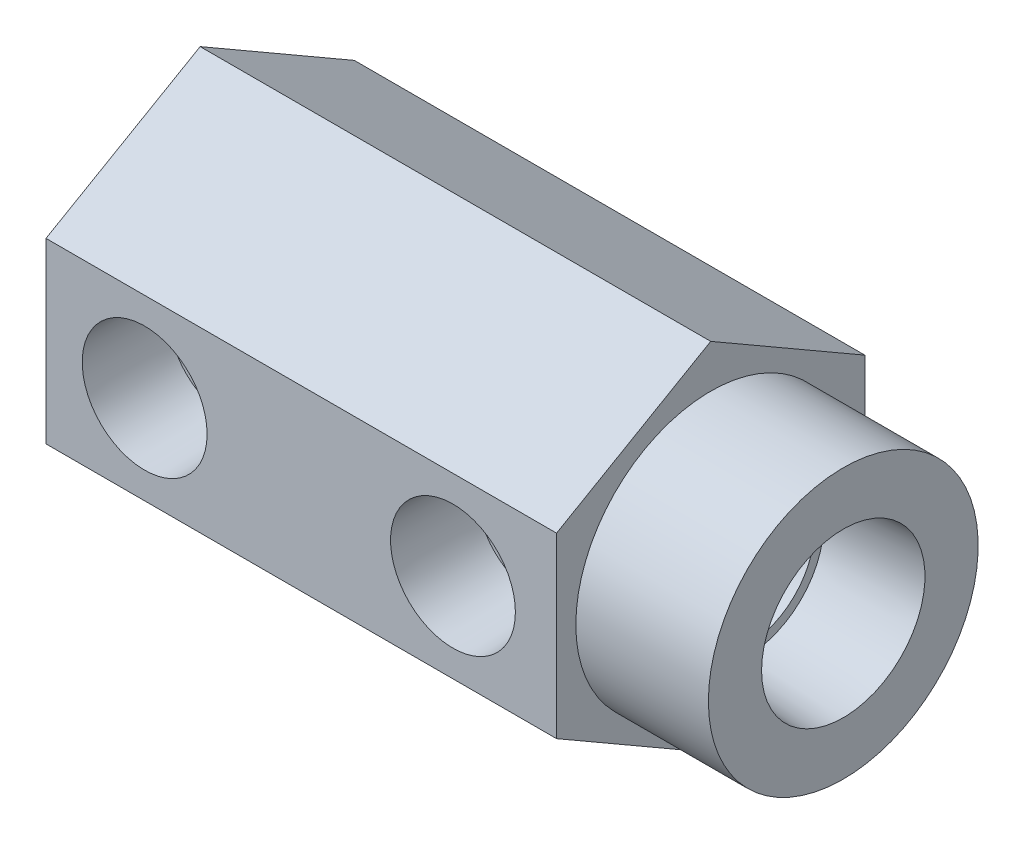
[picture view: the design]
ISO-10303-21;
HEADER;
FILE_DESCRIPTION(('STEP AP214'),'2;1');
FILE_NAME('part.step','',(''),(''),'','','');
FILE_SCHEMA(('AUTOMOTIVE_DESIGN { 1 0 10303 214 1 1 1 1 }'));
ENDSEC;
DATA;
#1=APPLICATION_CONTEXT('core data for automotive mechanical design processes');
#2=APPLICATION_PROTOCOL_DEFINITION('international standard','automotive_design',2000,#1);
#3=PRODUCT_CONTEXT('',#1,'mechanical');
#4=PRODUCT('Part','Part','',(#3));
#5=PRODUCT_RELATED_PRODUCT_CATEGORY('part','',(#4));
#6=PRODUCT_DEFINITION_FORMATION('','',#4);
#7=PRODUCT_DEFINITION_CONTEXT('part definition',#1,'design');
#8=PRODUCT_DEFINITION('design','',#6,#7);
#9=PRODUCT_DEFINITION_SHAPE('','',#8);
#10=(LENGTH_UNIT() NAMED_UNIT(*) SI_UNIT(.MILLI.,.METRE.));
#11=(NAMED_UNIT(*) PLANE_ANGLE_UNIT() SI_UNIT($,.RADIAN.));
#12=(NAMED_UNIT(*) SI_UNIT($,.STERADIAN.) SOLID_ANGLE_UNIT());
#13=UNCERTAINTY_MEASURE_WITH_UNIT(LENGTH_MEASURE(1.E-05),#10,'distance_accuracy_value','');
#14=(GEOMETRIC_REPRESENTATION_CONTEXT(3) GLOBAL_UNCERTAINTY_ASSIGNED_CONTEXT((#13)) GLOBAL_UNIT_ASSIGNED_CONTEXT((#10,
#11,#12)) REPRESENTATION_CONTEXT('',''));
#15=CARTESIAN_POINT('',(0.,0.,0.));
#16=DIRECTION('',(0.,0.,1.));
#17=DIRECTION('',(1.,0.,0.));
#18=AXIS2_PLACEMENT_3D('',#15,#16,#17);
#19=CARTESIAN_POINT('',(52.9844,0.,0.));
#20=DIRECTION('',(1.,0.,0.));
#21=DIRECTION('',(0.,0.,-1.));
#22=AXIS2_PLACEMENT_3D('',#19,#20,#21);
#23=CYLINDRICAL_SURFACE('',#22,3.17499999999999);
#24=CARTESIAN_POINT('',(16.4084,0.,0.));
#25=DIRECTION('',(1.,0.,0.));
#26=DIRECTION('',(0.,0.,-1.));
#27=AXIS2_PLACEMENT_3D('',#24,#25,#26);
#28=CIRCLE('',#27,3.17499999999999);
#29=CARTESIAN_POINT('',(16.4084,0.,-3.17499999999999));
#30=VERTEX_POINT('',#29);
#31=EDGE_CURVE('E145',#30,#30,#28,.T.);
#32=ORIENTED_EDGE('',*,*,#31,.F.);
#33=EDGE_LOOP('',(#32));
#34=FACE_BOUND('',#33,.T.);
#35=CARTESIAN_POINT('',(27.5844,0.,0.));
#36=DIRECTION('',(1.,0.,0.));
#37=DIRECTION('',(0.,0.,-1.));
#38=AXIS2_PLACEMENT_3D('',#35,#36,#37);
#39=CIRCLE('',#38,3.17499999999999);
#40=CARTESIAN_POINT('',(27.5844,0.,-3.17499999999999));
#41=VERTEX_POINT('',#40);
#42=EDGE_CURVE('E39',#41,#41,#39,.F.);
#43=ORIENTED_EDGE('',*,*,#42,.F.);
#44=EDGE_LOOP('',(#43));
#45=FACE_BOUND('',#44,.T.);
#46=ADVANCED_FACE('F35',(#34,#45),#23,.F.);
#47=CARTESIAN_POINT('',(33.528,0.,12.7));
#48=DIRECTION('',(0.,0.,1.));
#49=DIRECTION('',(1.,0.,0.));
#50=AXIS2_PLACEMENT_3D('',#47,#48,#49);
#51=CYLINDRICAL_SURFACE('',#50,4.2164);
#52=CARTESIAN_POINT('',(33.528,0.,5.77596));
#53=DIRECTION('',(0.,0.,1.));
#54=DIRECTION('',(1.,0.,0.));
#55=AXIS2_PLACEMENT_3D('',#52,#53,#54);
#56=CIRCLE('',#55,4.2164);
#57=CARTESIAN_POINT('',(37.7444,0.,5.77596));
#58=VERTEX_POINT('',#57);
#59=EDGE_CURVE('E286',#58,#58,#56,.T.);
#60=ORIENTED_EDGE('',*,*,#59,.T.);
#61=EDGE_LOOP('',(#60));
#62=FACE_BOUND('',#61,.T.);
#63=CARTESIAN_POINT('',(37.7444,0.,5.54990000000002));
#64=CARTESIAN_POINT('',(37.7443993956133,0.102666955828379,5.54989942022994));
#65=CARTESIAN_POINT('',(37.7406438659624,0.205343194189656,5.54704470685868));
#66=CARTESIAN_POINT('',(37.7256842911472,0.409877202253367,5.53569249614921));
#67=CARTESIAN_POINT('',(37.7144766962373,0.511734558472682,5.52719230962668));
#68=CARTESIAN_POINT('',(37.6847756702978,0.713930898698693,5.50472974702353));
#69=CARTESIAN_POINT('',(37.6662712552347,0.814267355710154,5.49075913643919));
#70=CARTESIAN_POINT('',(37.6222775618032,1.01254840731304,5.45767930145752));
#71=CARTESIAN_POINT('',(37.5967851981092,1.11049192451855,5.43856780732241));
#72=CARTESIAN_POINT('',(37.5107274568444,1.398497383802,5.37438339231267));
#73=CARTESIAN_POINT('',(37.440361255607,1.58418379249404,5.32229076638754));
#74=CARTESIAN_POINT('',(37.276841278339,1.93974746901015,5.2032718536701));
#75=CARTESIAN_POINT('',(37.1836912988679,2.10962736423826,5.1363480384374));
#76=CARTESIAN_POINT('',(36.9680945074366,2.44693461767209,4.98509307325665));
#77=CARTESIAN_POINT('',(36.8437265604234,2.61265837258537,4.89972096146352));
#78=CARTESIAN_POINT('',(36.5743774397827,2.92229860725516,4.72159970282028));
#79=CARTESIAN_POINT('',(36.4293655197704,3.06618188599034,4.62883964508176));
#80=CARTESIAN_POINT('',(36.1818679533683,3.27873581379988,4.47894046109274));
#81=CARTESIAN_POINT('',(36.0852396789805,3.35465016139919,4.4222195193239));
#82=CARTESIAN_POINT('',(35.8853172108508,3.49803153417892,4.30969399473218));
#83=CARTESIAN_POINT('',(35.7820209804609,3.56549595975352,4.25388969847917));
#84=CARTESIAN_POINT('',(35.5689644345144,3.69158445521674,4.14494021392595));
#85=CARTESIAN_POINT('',(35.459210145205,3.75021659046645,4.091792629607));
#86=CARTESIAN_POINT('',(35.2332788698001,3.85820397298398,3.99013143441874));
#87=CARTESIAN_POINT('',(35.1171056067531,3.90756452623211,3.94161518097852));
#88=CARTESIAN_POINT('',(34.8423535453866,4.00972513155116,3.83800214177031));
#89=CARTESIAN_POINT('',(34.6815147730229,4.05910874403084,3.78530268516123));
#90=CARTESIAN_POINT('',(34.4334747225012,4.11890503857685,3.71979682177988));
#91=CARTESIAN_POINT('',(34.3497154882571,4.13645117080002,3.70022626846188));
#92=CARTESIAN_POINT('',(34.1802742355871,4.16652842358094,3.66632583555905));
#93=CARTESIAN_POINT('',(34.0945932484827,4.17906216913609,3.65199321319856));
#94=CARTESIAN_POINT('',(33.9209530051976,4.19896788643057,3.62908998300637));
#95=CARTESIAN_POINT('',(33.8329793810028,4.2062854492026,3.62058014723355));
#96=CARTESIAN_POINT('',(33.6563570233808,4.2153732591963,3.60999553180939));
#97=CARTESIAN_POINT('',(33.5677083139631,4.21714370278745,3.60792052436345));
#98=CARTESIAN_POINT('',(33.3905433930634,4.21508975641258,3.61032018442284));
#99=CARTESIAN_POINT('',(33.3020272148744,4.21126414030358,3.61479628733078));
#100=CARTESIAN_POINT('',(33.1259748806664,4.1981195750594,3.63005192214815));
#101=CARTESIAN_POINT('',(33.038438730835,4.18880059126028,3.64083149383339));
#102=CARTESIAN_POINT('',(32.7985166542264,4.15568903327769,3.67868158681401));
#103=CARTESIAN_POINT('',(32.6478348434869,4.1262776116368,3.71190594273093));
#104=CARTESIAN_POINT('',(32.3540921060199,4.05253036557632,3.79227022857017));
#105=CARTESIAN_POINT('',(32.211039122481,4.00817932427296,3.83942434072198));
#106=CARTESIAN_POINT('',(31.9583831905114,3.91523448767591,3.93394303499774));
#107=CARTESIAN_POINT('',(31.847374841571,3.86881960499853,3.97976043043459));
#108=CARTESIAN_POINT('',(31.6311954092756,3.7675481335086,4.07576238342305));
#109=CARTESIAN_POINT('',(31.5260274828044,3.71268703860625,4.12594926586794));
#110=CARTESIAN_POINT('',(31.3214051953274,3.5948485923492,4.22901830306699));
#111=CARTESIAN_POINT('',(31.2219633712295,3.53185434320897,4.28190592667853));
#112=CARTESIAN_POINT('',(31.0290973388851,3.39812936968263,4.38878526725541));
#113=CARTESIAN_POINT('',(30.9356721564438,3.32739990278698,4.44277680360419));
#114=CARTESIAN_POINT('',(30.7523590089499,3.17621734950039,4.55214005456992));
#115=CARTESIAN_POINT('',(30.662649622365,3.09554338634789,4.60750688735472));
#116=CARTESIAN_POINT('',(30.4900225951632,2.92631985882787,4.7168012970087));
#117=CARTESIAN_POINT('',(30.4071076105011,2.83776724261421,4.77072830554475));
#118=CARTESIAN_POINT('',(30.1695373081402,2.56081846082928,4.92833957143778));
#119=CARTESIAN_POINT('',(30.0255232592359,2.36069403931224,5.02818332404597));
#120=CARTESIAN_POINT('',(29.79622654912,1.97290355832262,5.19079382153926));
#121=CARTESIAN_POINT('',(29.704976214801,1.79022627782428,5.25699864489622));
#122=CARTESIAN_POINT('',(29.5877201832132,1.50428240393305,5.34307696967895));
#123=CARTESIAN_POINT('',(29.5518975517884,1.40695118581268,5.36957042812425));
#124=CARTESIAN_POINT('',(29.487255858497,1.20882529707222,5.41761054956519));
#125=CARTESIAN_POINT('',(29.4584337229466,1.10803216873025,5.43915938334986));
#126=CARTESIAN_POINT('',(29.4080388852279,0.902877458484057,5.47696644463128));
#127=CARTESIAN_POINT('',(29.3865198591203,0.798495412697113,5.49318547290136));
#128=CARTESIAN_POINT('',(29.3513945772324,0.587711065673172,5.5197156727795));
#129=CARTESIAN_POINT('',(29.3377846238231,0.481309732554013,5.53002960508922));
#130=CARTESIAN_POINT('',(29.3187165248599,0.267379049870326,5.54449183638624));
#131=CARTESIAN_POINT('',(29.3132569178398,0.159849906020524,5.54864124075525));
#132=CARTESIAN_POINT('',(29.31059043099,-0.0553630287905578,5.55066695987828));
#133=CARTESIAN_POINT('',(29.3133828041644,-0.163046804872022,5.54854384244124));
#134=CARTESIAN_POINT('',(29.3264157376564,-0.365919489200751,5.53865106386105));
#135=CARTESIAN_POINT('',(29.3358141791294,-0.461194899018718,5.5315198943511));
#136=CARTESIAN_POINT('',(29.3609746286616,-0.65042738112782,5.51247648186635));
#137=CARTESIAN_POINT('',(29.3767386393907,-0.744384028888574,5.50056273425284));
#138=CARTESIAN_POINT('',(29.4332697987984,-1.02327908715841,5.4579792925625));
#139=CARTESIAN_POINT('',(29.4832871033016,-1.20540685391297,5.42045882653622));
#140=CARTESIAN_POINT('',(29.6070842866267,-1.56242729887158,5.32871242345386));
#141=CARTESIAN_POINT('',(29.6814572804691,-1.73700152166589,5.27407116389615));
#142=CARTESIAN_POINT('',(29.8505450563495,-2.07109183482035,5.15204916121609));
#143=CARTESIAN_POINT('',(29.9452628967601,-2.23060565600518,5.08466650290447));
#144=CARTESIAN_POINT('',(30.1694079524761,-2.55802504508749,4.92909083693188));
#145=CARTESIAN_POINT('',(30.3019810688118,-2.72300325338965,4.83929765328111));
#146=CARTESIAN_POINT('',(30.5883037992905,-3.02991540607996,4.65330404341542));
#147=CARTESIAN_POINT('',(30.7420960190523,-3.17180170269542,4.55709093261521));
#148=CARTESIAN_POINT('',(31.0034639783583,-3.3794070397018,4.40345363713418));
#149=CARTESIAN_POINT('',(31.1049126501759,-3.45288781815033,4.34591141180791));
#150=CARTESIAN_POINT('',(31.314685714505,-3.5909673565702,4.23253042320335));
#151=CARTESIAN_POINT('',(31.4230125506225,-3.65556293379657,4.17669227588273));
#152=CARTESIAN_POINT('',(31.6462598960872,-3.7753266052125,4.06875742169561));
#153=CARTESIAN_POINT('',(31.7611678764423,-3.83051186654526,4.01665400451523));
#154=CARTESIAN_POINT('',(31.9975785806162,-3.93094643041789,3.91841531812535));
#155=CARTESIAN_POINT('',(32.1190762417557,-3.97620322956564,3.87227555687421));
#156=CARTESIAN_POINT('',(32.3974988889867,-4.06520982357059,3.77896121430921));
#157=CARTESIAN_POINT('',(32.5561211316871,-4.10619306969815,3.7340128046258));
#158=CARTESIAN_POINT('',(32.7996105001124,-4.15383268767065,3.68070998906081));
#159=CARTESIAN_POINT('',(32.8816471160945,-4.16740255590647,3.66530086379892));
#160=CARTESIAN_POINT('',(33.0471718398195,-4.18972486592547,3.63976459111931));
#161=CARTESIAN_POINT('',(33.1306592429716,-4.19847958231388,3.62963494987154));
#162=CARTESIAN_POINT('',(33.2991320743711,-4.21103758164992,3.61505835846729));
#163=CARTESIAN_POINT('',(33.3841240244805,-4.21480358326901,3.6106542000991));
#164=CARTESIAN_POINT('',(33.5542775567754,-4.21717640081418,3.60788260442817));
#165=CARTESIAN_POINT('',(33.639439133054,-4.21578339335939,3.60951496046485));
#166=CARTESIAN_POINT('',(33.8092521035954,-4.20786839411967,3.61873867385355));
#167=CARTESIAN_POINT('',(33.8939031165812,-4.20134295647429,3.62633403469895));
#168=CARTESIAN_POINT('',(34.0620056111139,-4.18330254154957,3.64713005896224));
#169=CARTESIAN_POINT('',(34.1454564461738,-4.17178497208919,3.66033363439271));
#170=CARTESIAN_POINT('',(34.3240534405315,-4.1417155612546,3.69434379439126));
#171=CARTESIAN_POINT('',(34.4188890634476,-4.12232321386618,3.71603879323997));
#172=CARTESIAN_POINT('',(34.6056232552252,-4.07749843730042,3.7651699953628));
#173=CARTESIAN_POINT('',(34.697519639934,-4.05206162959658,3.79261035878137));
#174=CARTESIAN_POINT('',(34.9685718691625,-3.96719813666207,3.88193715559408));
#175=CARTESIAN_POINT('',(35.1428493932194,-3.89926066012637,3.95077814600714));
#176=CARTESIAN_POINT('',(35.426054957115,-3.76720881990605,4.07616702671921));
#177=CARTESIAN_POINT('',(35.5387046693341,-3.70824622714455,4.13006200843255));
#178=CARTESIAN_POINT('',(35.7572672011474,-3.5811127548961,4.24076863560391));
#179=CARTESIAN_POINT('',(35.8631775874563,-3.51293857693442,4.29758132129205));
#180=CARTESIAN_POINT('',(36.0681950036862,-3.36767607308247,4.41233843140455));
#181=CARTESIAN_POINT('',(36.167295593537,-3.29057948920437,4.47028386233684));
#182=CARTESIAN_POINT('',(36.3583871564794,-3.12772920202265,4.58570164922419));
#183=CARTESIAN_POINT('',(36.450379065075,-3.04197664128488,4.64317406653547));
#184=CARTESIAN_POINT('',(36.6281804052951,-2.86064113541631,4.75707411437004));
#185=CARTESIAN_POINT('',(36.7138800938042,-2.76493305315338,4.81347428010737));
#186=CARTESIAN_POINT('',(36.8770160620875,-2.56491197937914,4.9229681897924));
#187=CARTESIAN_POINT('',(36.954451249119,-2.46059785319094,4.9760614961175));
#188=CARTESIAN_POINT('',(37.100127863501,-2.24386878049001,5.07747289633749));
#189=CARTESIAN_POINT('',(37.1683863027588,-2.13146943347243,5.12579978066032));
#190=CARTESIAN_POINT('',(37.29491910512,-1.89890802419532,5.21642520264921));
#191=CARTESIAN_POINT('',(37.3531981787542,-1.77874966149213,5.25872658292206));
#192=CARTESIAN_POINT('',(37.4439058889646,-1.56622364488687,5.32513054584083));
#193=CARTESIAN_POINT('',(37.4789964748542,-1.47553606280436,5.35100662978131));
#194=CARTESIAN_POINT('',(37.5430944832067,-1.29096184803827,5.39850728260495));
#195=CARTESIAN_POINT('',(37.5721033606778,-1.19707598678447,5.420132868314));
#196=CARTESIAN_POINT('',(37.6236159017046,-1.00680382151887,5.4586756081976));
#197=CARTESIAN_POINT('',(37.6461329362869,-0.910423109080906,5.47560243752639));
#198=CARTESIAN_POINT('',(37.6844114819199,-0.715624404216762,5.50444899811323));
#199=CARTESIAN_POINT('',(37.700175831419,-0.61720728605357,5.5163708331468));
#200=CARTESIAN_POINT('',(37.7230526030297,-0.432452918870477,5.53369497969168));
#201=CARTESIAN_POINT('',(37.7310480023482,-0.34628607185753,5.53976185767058));
#202=CARTESIAN_POINT('',(37.7417225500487,-0.173415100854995,5.54786506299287));
#203=CARTESIAN_POINT('',(37.7444005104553,-0.0867108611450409,5.54990048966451));
#204=CARTESIAN_POINT('',(37.7444,0.,5.54990000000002));
#205=B_SPLINE_CURVE_WITH_KNOTS('',3,(#63,#64,#65,#66,#67,#68,#69,#70,#71,#72,#73,#74,#75,#76,
#77,#78,#79,#80,#81,#82,#83,#84,#85,#86,#87,#88,#89,#90,#91,#92,#93,#94,#95,#96,#97,#98,#99,
#100,#101,#102,#103,#104,#105,#106,#107,#108,#109,#110,#111,#112,#113,#114,#115,#116,#117,#118,
#119,#120,#121,#122,#123,#124,#125,#126,#127,#128,#129,#130,#131,#132,#133,#134,#135,#136,#137,
#138,#139,#140,#141,#142,#143,#144,#145,#146,#147,#148,#149,#150,#151,#152,#153,#154,#155,#156,
#157,#158,#159,#160,#161,#162,#163,#164,#165,#166,#167,#168,#169,#170,#171,#172,#173,#174,#175,
#176,#177,#178,#179,#180,#181,#182,#183,#184,#185,#186,#187,#188,#189,#190,#191,#192,#193,#194,
#195,#196,#197,#198,#199,#200,#201,#202,#203,#204),.UNSPECIFIED.,.T.,.F.,(4,2,2,2,2,2,2,2,2,2,2,
2,2,2,2,2,2,2,2,2,2,2,2,2,2,2,2,2,2,2,2,2,2,2,2,2,2,2,2,2,2,2,2,2,2,2,2,2,2,2,2,2,2,2,2,2,2,2,2,
2,2,2,2,2,2,2,2,2,2,2,4),(0.,0.307909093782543,0.615964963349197,0.924486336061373,
1.23314414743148,1.84608968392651,2.45893315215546,3.12888302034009,3.79984133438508,
4.20549409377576,4.61127134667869,5.01667578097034,5.42184749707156,5.94866107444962,
6.21175949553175,6.47471995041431,6.74038467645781,7.00603999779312,7.2717535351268,
7.53746874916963,8.00678580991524,8.47658235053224,8.86232249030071,9.24826914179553,
9.63503095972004,10.0217299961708,10.4195319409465,10.817488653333,11.6111347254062,
12.2523588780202,12.5731486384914,12.8937972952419,13.2167540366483,13.5395596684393,
13.8623074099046,14.1850259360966,14.4726847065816,14.7604340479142,15.3354443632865,
15.925652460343,16.5159493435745,17.2032337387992,17.891918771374,18.3050679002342,
18.7183646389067,19.1308991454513,19.543121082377,20.0506303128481,20.3040712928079,
20.5573924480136,20.8125962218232,21.0677912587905,21.323157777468,21.5786570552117,
21.8757972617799,22.1731533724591,22.7686074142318,23.1824806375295,23.5965024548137,
24.0109105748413,24.4252640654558,24.8456610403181,25.266113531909,25.6857755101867,
26.1052388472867,26.4068178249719,26.7083245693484,27.0092058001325,27.3099604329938,
27.5699574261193,27.8300124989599),.UNSPECIFIED.);
#206=CARTESIAN_POINT('',(37.7444,0.,5.54990000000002));
#207=VERTEX_POINT('',#206);
#208=EDGE_CURVE('E157',#207,#207,#205,.T.);
#209=ORIENTED_EDGE('',*,*,#208,.F.);
#210=EDGE_LOOP('',(#209));
#211=FACE_BOUND('',#210,.T.);
#212=ADVANCED_FACE('F189',(#62,#211),#51,.F.);
#213=CARTESIAN_POINT('',(52.9844,0.,0.));
#214=DIRECTION('',(1.,0.,0.));
#215=DIRECTION('',(0.,0.,-1.));
#216=AXIS2_PLACEMENT_3D('',#213,#214,#215);
#217=PLANE('',#216);
#218=CARTESIAN_POINT('',(52.9844,0.,0.));
#219=DIRECTION('',(1.,0.,0.));
#220=DIRECTION('',(0.,0.,-1.));
#221=AXIS2_PLACEMENT_3D('',#218,#219,#220);
#222=CIRCLE('',#221,11.1125);
#223=CARTESIAN_POINT('',(52.9844,0.,11.1125));
#224=VERTEX_POINT('',#223);
#225=EDGE_CURVE('E279',#224,#224,#222,.T.);
#226=ORIENTED_EDGE('',*,*,#225,.T.);
#227=EDGE_LOOP('',(#226));
#228=FACE_BOUND('',#227,.T.);
#229=CARTESIAN_POINT('',(52.9844,0.,0.));
#230=DIRECTION('',(-1.,0.,0.));
#231=DIRECTION('',(0.,0.,1.));
#232=AXIS2_PLACEMENT_3D('',#229,#230,#231);
#233=CIRCLE('',#232,6.73100000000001);
#234=CARTESIAN_POINT('',(52.9844,0.,6.73100000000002));
#235=VERTEX_POINT('',#234);
#236=EDGE_CURVE('E311',#235,#235,#233,.T.);
#237=ORIENTED_EDGE('',*,*,#236,.T.);
#238=EDGE_LOOP('',(#237));
#239=FACE_BOUND('',#238,.T.);
#240=ADVANCED_FACE('F233',(#228,#239),#217,.T.);
#241=CARTESIAN_POINT('',(16.4084,0.,0.));
#242=DIRECTION('',(1.,0.,0.));
#243=DIRECTION('',(0.,0.,-1.));
#244=AXIS2_PLACEMENT_3D('',#241,#242,#243);
#245=CONICAL_SURFACE('',#244,3.17499999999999,1.02974425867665);
#246=CARTESIAN_POINT('',(16.1699334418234,0.,0.));
#247=DIRECTION('',(1.,0.,0.));
#248=DIRECTION('',(0.,0.,-1.));
#249=AXIS2_PLACEMENT_3D('',#246,#247,#248);
#250=CIRCLE('',#249,2.77812499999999);
#251=CARTESIAN_POINT('',(16.1699334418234,0.,-2.77812499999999));
#252=VERTEX_POINT('',#251);
#253=EDGE_CURVE('E142',#252,#252,#250,.F.);
#254=ORIENTED_EDGE('',*,*,#253,.T.);
#255=EDGE_LOOP('',(#254));
#256=FACE_BOUND('',#255,.T.);
#257=ORIENTED_EDGE('',*,*,#31,.T.);
#258=EDGE_LOOP('',(#257));
#259=FACE_BOUND('',#258,.T.);
#260=ADVANCED_FACE('F238',(#256,#259),#245,.F.);
#261=CARTESIAN_POINT('',(52.9844,0.,0.));
#262=DIRECTION('',(1.,0.,0.));
#263=DIRECTION('',(0.,0.,-1.));
#264=AXIS2_PLACEMENT_3D('',#261,#262,#263);
#265=CYLINDRICAL_SURFACE('',#264,2.77812499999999);
#266=CARTESIAN_POINT('',(12.3444,0.,-2.77812499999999));
#267=CARTESIAN_POINT('',(12.3443955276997,-0.139883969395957,-2.77811997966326));
#268=CARTESIAN_POINT('',(12.3373755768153,-0.279800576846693,-2.76749868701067));
#269=CARTESIAN_POINT('',(12.3099836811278,-0.555187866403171,-2.72565235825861));
#270=CARTESIAN_POINT('',(12.2896031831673,-0.6906556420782,-2.69441412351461));
#271=CARTESIAN_POINT('',(12.2375104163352,-0.952754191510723,-2.61323304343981));
#272=CARTESIAN_POINT('',(12.2058514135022,-1.07942321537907,-2.56337806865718));
#273=CARTESIAN_POINT('',(12.1337605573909,-1.32210407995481,-2.44706908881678));
#274=CARTESIAN_POINT('',(12.0933275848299,-1.4381145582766,-2.38061296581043));
#275=CARTESIAN_POINT('',(12.0029110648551,-1.66718281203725,-2.22689910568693));
#276=CARTESIAN_POINT('',(11.9524106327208,-1.77917454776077,-2.13836318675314));
#277=CARTESIAN_POINT('',(11.8482905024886,-1.98773409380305,-1.94603559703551));
#278=CARTESIAN_POINT('',(11.7946664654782,-2.08427971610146,-1.84222238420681));
#279=CARTESIAN_POINT('',(11.680384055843,-2.27435151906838,-1.60375038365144));
#280=CARTESIAN_POINT('',(11.6199096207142,-2.36513867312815,-1.46680289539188));
#281=CARTESIAN_POINT('',(11.5081634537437,-2.52226630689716,-1.17614753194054));
#282=CARTESIAN_POINT('',(11.4568758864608,-2.58864906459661,-1.0224692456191));
#283=CARTESIAN_POINT('',(11.3845681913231,-2.6786449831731,-0.746661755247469));
#284=CARTESIAN_POINT('',(11.3590896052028,-2.70904686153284,-0.627927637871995));
#285=CARTESIAN_POINT('',(11.3208802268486,-2.75398593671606,-0.385574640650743));
#286=CARTESIAN_POINT('',(11.3081282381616,-2.76854951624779,-0.261964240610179));
#287=CARTESIAN_POINT('',(11.2973346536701,-2.78090423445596,-0.0127670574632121));
#288=CARTESIAN_POINT('',(11.299348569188,-2.77863208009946,0.112825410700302));
#289=CARTESIAN_POINT('',(11.3178791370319,-2.75733196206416,0.361533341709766));
#290=CARTESIAN_POINT('',(11.3344080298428,-2.73828985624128,0.484646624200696));
#291=CARTESIAN_POINT('',(11.3785253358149,-2.68574292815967,0.720261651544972));
#292=CARTESIAN_POINT('',(11.405649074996,-2.65284171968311,0.832990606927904));
#293=CARTESIAN_POINT('',(11.4678512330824,-2.57408907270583,1.05144792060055));
#294=CARTESIAN_POINT('',(11.5029322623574,-2.52823338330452,1.15717396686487));
#295=CARTESIAN_POINT('',(11.5855849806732,-2.41433509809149,1.38122293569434));
#296=CARTESIAN_POINT('',(11.6342504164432,-2.34368656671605,1.49781446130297));
#297=CARTESIAN_POINT('',(11.7342078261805,-2.18677186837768,1.71883915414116));
#298=CARTESIAN_POINT('',(11.7855029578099,-2.10048659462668,1.82325718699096));
#299=CARTESIAN_POINT('',(11.8972440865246,-1.89401186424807,2.0389531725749));
#300=CARTESIAN_POINT('',(11.9574048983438,-1.77049887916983,2.14723280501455));
#301=CARTESIAN_POINT('',(12.0697093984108,-1.50393214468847,2.3416440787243));
#302=CARTESIAN_POINT('',(12.1218609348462,-1.360897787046,2.42779745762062));
#303=CARTESIAN_POINT('',(12.2035712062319,-1.08804954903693,2.55975410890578));
#304=CARTESIAN_POINT('',(12.2355572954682,-0.961193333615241,2.61016446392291));
#305=CARTESIAN_POINT('',(12.2881429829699,-0.699302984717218,2.69216201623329));
#306=CARTESIAN_POINT('',(12.3087520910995,-0.564275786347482,2.72376493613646));
#307=CARTESIAN_POINT('',(12.3367594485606,-0.289077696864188,2.76656311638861));
#308=CARTESIAN_POINT('',(12.3441045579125,-0.148888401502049,2.77767629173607));
#309=CARTESIAN_POINT('',(12.3446777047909,0.131592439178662,2.77854678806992));
#310=CARTESIAN_POINT('',(12.3379061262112,0.271883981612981,2.76830468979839));
#311=CARTESIAN_POINT('',(12.3118222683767,0.53898974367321,2.72846498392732));
#312=CARTESIAN_POINT('',(12.293354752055,0.666086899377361,2.70017031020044));
#313=CARTESIAN_POINT('',(12.2462164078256,0.913332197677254,2.62686914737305));
#314=CARTESIAN_POINT('',(12.2175439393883,1.03347921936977,2.58185997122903));
#315=CARTESIAN_POINT('',(12.1499536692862,1.27211922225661,2.47345398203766));
#316=CARTESIAN_POINT('',(12.1104913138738,1.38999773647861,2.40905262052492));
#317=CARTESIAN_POINT('',(12.0252151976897,1.61372348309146,2.26530005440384));
#318=CARTESIAN_POINT('',(11.9793972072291,1.7195626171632,2.18593888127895));
#319=CARTESIAN_POINT('',(11.8769809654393,1.93374575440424,2.00042955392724));
#320=CARTESIAN_POINT('',(11.819819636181,2.03987372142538,1.89203198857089));
#321=CARTESIAN_POINT('',(11.7060872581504,2.23336504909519,1.65921349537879));
#322=CARTESIAN_POINT('',(11.6495165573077,2.32071788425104,1.53478364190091));
#323=CARTESIAN_POINT('',(11.5483307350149,2.46707513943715,1.28464793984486));
#324=CARTESIAN_POINT('',(11.5030847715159,2.52806065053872,1.16036269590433));
#325=CARTESIAN_POINT('',(11.4230252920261,2.63156603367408,0.901230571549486));
#326=CARTESIAN_POINT('',(11.3881929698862,2.67411925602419,0.766403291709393));
#327=CARTESIAN_POINT('',(11.3387874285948,2.7331509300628,0.511839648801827));
#328=CARTESIAN_POINT('',(11.321811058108,2.75278516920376,0.393313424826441));
#329=CARTESIAN_POINT('',(11.3012384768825,2.77648205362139,0.153603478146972));
#330=CARTESIAN_POINT('',(11.2976297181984,2.78055930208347,0.0324223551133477));
#331=CARTESIAN_POINT('',(11.3043444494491,2.77288356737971,-0.209018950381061));
#332=CARTESIAN_POINT('',(11.3146671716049,2.76113145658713,-0.329279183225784));
#333=CARTESIAN_POINT('',(11.347667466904,2.7225709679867,-0.565663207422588));
#334=CARTESIAN_POINT('',(11.3703613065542,2.6957427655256,-0.681781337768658));
#335=CARTESIAN_POINT('',(11.4329033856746,2.61891416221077,-0.939151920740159));
#336=CARTESIAN_POINT('',(11.4757744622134,2.564531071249,-1.07834904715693));
#337=CARTESIAN_POINT('',(11.5704785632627,2.43592687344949,-1.34390911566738));
#338=CARTESIAN_POINT('',(11.6223239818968,2.36167825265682,-1.47025391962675));
#339=CARTESIAN_POINT('',(11.7301621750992,2.19375835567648,-1.71092773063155));
#340=CARTESIAN_POINT('',(11.7862104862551,2.09977824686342,-1.82501585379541));
#341=CARTESIAN_POINT('',(11.8966286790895,1.89448963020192,-2.03733294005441));
#342=CARTESIAN_POINT('',(11.9509980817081,1.78317623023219,-2.13555740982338));
#343=CARTESIAN_POINT('',(12.0599078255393,1.52949387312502,-2.32521006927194));
#344=CARTESIAN_POINT('',(12.1136453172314,1.38498877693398,-2.41431318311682));
#345=CARTESIAN_POINT('',(12.1837916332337,1.15543155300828,-2.52789646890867));
#346=CARTESIAN_POINT('',(12.205427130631,1.07679625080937,-2.5624074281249));
#347=CARTESIAN_POINT('',(12.2445786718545,0.915786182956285,-2.62426099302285));
#348=CARTESIAN_POINT('',(12.2620964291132,0.833412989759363,-2.6516065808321));
#349=CARTESIAN_POINT('',(12.2990312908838,0.628891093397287,-2.70889840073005));
#350=CARTESIAN_POINT('',(12.3159311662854,0.505095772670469,-2.73475594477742));
#351=CARTESIAN_POINT('',(12.3386147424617,0.254208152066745,-2.76936720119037));
#352=CARTESIAN_POINT('',(12.3444040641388,0.127117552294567,-2.77812956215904));
#353=CARTESIAN_POINT('',(12.3444,0.,-2.77812499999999));
#354=B_SPLINE_CURVE_WITH_KNOTS('',3,(#266,#267,#268,#269,#270,#271,#272,#273,#274,#275,#276,
#277,#278,#279,#280,#281,#282,#283,#284,#285,#286,#287,#288,#289,#290,#291,#292,#293,#294,#295,
#296,#297,#298,#299,#300,#301,#302,#303,#304,#305,#306,#307,#308,#309,#310,#311,#312,#313,#314,
#315,#316,#317,#318,#319,#320,#321,#322,#323,#324,#325,#326,#327,#328,#329,#330,#331,#332,#333,
#334,#335,#336,#337,#338,#339,#340,#341,#342,#343,#344,#345,#346,#347,#348,#349,#350,#351,#352,
#353),.UNSPECIFIED.,.T.,.F.,(4,2,2,2,2,2,2,2,2,2,2,2,2,2,2,2,2,2,2,2,2,2,2,2,2,2,2,2,2,2,2,2,2,
2,2,2,2,2,2,2,2,2,2,4),(0.,0.419152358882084,0.838573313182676,1.25603913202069,
1.67355823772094,2.12613857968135,2.57936331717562,3.10216790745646,3.62406247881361,
3.99811472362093,4.37154293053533,4.74637573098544,5.12152493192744,5.48179405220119,
5.84218152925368,6.27490955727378,6.70816995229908,7.23044654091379,7.75220804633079,
8.17104864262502,8.58953860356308,9.0097014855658,9.4298529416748,9.82266301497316,
10.2155362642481,10.6339311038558,11.0526057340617,11.5370187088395,12.0217025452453,
12.4570234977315,12.8915534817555,13.253952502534,13.6160112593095,13.9780500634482,
14.3405660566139,14.8044889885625,15.2690578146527,15.7415272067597,16.2141301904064,
16.744910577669,17.0101944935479,17.2753678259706,17.656459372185,18.0373580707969),.UNSPECIFIED.);
#355=CARTESIAN_POINT('',(12.3444,0.,-2.77812499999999));
#356=VERTEX_POINT('',#355);
#357=EDGE_CURVE('E147',#356,#356,#354,.T.);
#358=ORIENTED_EDGE('',*,*,#357,.T.);
#359=EDGE_LOOP('',(#358));
#360=FACE_BOUND('',#359,.T.);
#361=ORIENTED_EDGE('',*,*,#253,.F.);
#362=EDGE_LOOP('',(#361));
#363=FACE_BOUND('',#362,.T.);
#364=ADVANCED_FACE('F163',(#360,#363),#265,.F.);
#365=CARTESIAN_POINT('',(37.7444,0.,5.77596));
#366=DIRECTION('',(0.,0.,-1.));
#367=DIRECTION('',(-1.,0.,0.));
#368=AXIS2_PLACEMENT_3D('',#365,#366,#367);
#369=PLANE('',#368);
#370=ORIENTED_EDGE('',*,*,#59,.F.);
#371=EDGE_LOOP('',(#370));
#372=FACE_BOUND('',#371,.T.);
#373=CARTESIAN_POINT('',(33.528,0.,5.77596));
#374=DIRECTION('',(0.,0.,1.));
#375=DIRECTION('',(1.,0.,0.));
#376=AXIS2_PLACEMENT_3D('',#373,#374,#375);
#377=CIRCLE('',#376,4.93618496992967);
#378=CARTESIAN_POINT('',(38.4641849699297,0.,5.77596));
#379=VERTEX_POINT('',#378);
#380=EDGE_CURVE('E289',#379,#379,#377,.T.);
#381=ORIENTED_EDGE('',*,*,#380,.T.);
#382=EDGE_LOOP('',(#381));
#383=FACE_BOUND('',#382,.T.);
#384=ADVANCED_FACE('F180',(#372,#383),#369,.F.);
#385=CARTESIAN_POINT('',(33.528,0.,12.7));
#386=DIRECTION('',(0.,0.,1.));
#387=DIRECTION('',(1.,0.,0.));
#388=AXIS2_PLACEMENT_3D('',#385,#386,#387);
#389=CONICAL_SURFACE('',#388,5.1435,0.0299323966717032);
#390=ORIENTED_EDGE('',*,*,#380,.F.);
#391=EDGE_LOOP('',(#390));
#392=FACE_BOUND('',#391,.T.);
#393=CARTESIAN_POINT('',(33.528,0.,12.7));
#394=DIRECTION('',(0.,0.,1.));
#395=DIRECTION('',(1.,0.,0.));
#396=AXIS2_PLACEMENT_3D('',#393,#394,#395);
#397=CIRCLE('',#396,5.1435);
#398=CARTESIAN_POINT('',(38.6715,0.,12.7));
#399=VERTEX_POINT('',#398);
#400=EDGE_CURVE('E155',#399,#399,#397,.T.);
#401=ORIENTED_EDGE('',*,*,#400,.T.);
#402=EDGE_LOOP('',(#401));
#403=FACE_BOUND('',#402,.T.);
#404=ADVANCED_FACE('F176',(#392,#403),#389,.F.);
#405=CARTESIAN_POINT('',(42.0624,-14.6646968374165,0.));
#406=DIRECTION('',(0.,0.866025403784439,0.5));
#407=DIRECTION('',(0.,-0.5,0.866025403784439));
#408=AXIS2_PLACEMENT_3D('',#405,#406,#407);
#409=PLANE('',#408);
#410=DIRECTION('',(0.,0.5,-0.866025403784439));
#411=VECTOR('',#410,1.);
#412=CARTESIAN_POINT('',(0.,-14.6646968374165,0.));
#413=LINE('',#412,#411);
#414=CARTESIAN_POINT('',(0.,-14.6646968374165,0.));
#415=VERTEX_POINT('',#414);
#416=CARTESIAN_POINT('',(0.,-7.33234841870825,-12.7));
#417=VERTEX_POINT('',#416);
#418=EDGE_CURVE('E128',#415,#417,#413,.T.);
#419=ORIENTED_EDGE('',*,*,#418,.T.);
#420=DIRECTION('',(-1.,0.,0.));
#421=VECTOR('',#420,1.);
#422=CARTESIAN_POINT('',(42.0624,-7.33234841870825,-12.7));
#423=LINE('',#422,#421);
#424=CARTESIAN_POINT('',(42.0624,-7.33234841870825,-12.7));
#425=VERTEX_POINT('',#424);
#426=EDGE_CURVE('E45',#425,#417,#423,.T.);
#427=ORIENTED_EDGE('',*,*,#426,.F.);
#428=DIRECTION('',(0.,0.5,-0.866025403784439));
#429=VECTOR('',#428,1.);
#430=CARTESIAN_POINT('',(42.0624,-14.6646968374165,0.));
#431=LINE('',#430,#429);
#432=CARTESIAN_POINT('',(42.0624,-14.6646968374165,0.));
#433=VERTEX_POINT('',#432);
#434=EDGE_CURVE('E92',#433,#425,#431,.T.);
#435=ORIENTED_EDGE('',*,*,#434,.F.);
#436=DIRECTION('',(-1.,0.,0.));
#437=VECTOR('',#436,1.);
#438=CARTESIAN_POINT('',(42.0624,-14.6646968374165,0.));
#439=LINE('',#438,#437);
#440=EDGE_CURVE('E11',#433,#415,#439,.T.);
#441=ORIENTED_EDGE('',*,*,#440,.T.);
#442=EDGE_LOOP('',(#419,#427,#435,#441));
#443=FACE_BOUND('',#442,.T.);
#444=ADVANCED_FACE('F179',(#443),#409,.F.);
#445=CARTESIAN_POINT('',(42.0624,-7.33234841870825,-12.7));
#446=DIRECTION('',(0.,0.,1.));
#447=DIRECTION('',(1.,0.,0.));
#448=AXIS2_PLACEMENT_3D('',#445,#446,#447);
#449=PLANE('',#448);
#450=CARTESIAN_POINT('',(8.128,0.,-12.7));
#451=DIRECTION('',(0.,0.,-1.));
#452=DIRECTION('',(-1.,0.,0.));
#453=AXIS2_PLACEMENT_3D('',#450,#451,#452);
#454=CIRCLE('',#453,5.1435);
#455=CARTESIAN_POINT('',(2.9845,0.,-12.7));
#456=VERTEX_POINT('',#455);
#457=EDGE_CURVE('E308',#456,#456,#454,.T.);
#458=ORIENTED_EDGE('',*,*,#457,.F.);
#459=EDGE_LOOP('',(#458));
#460=FACE_BOUND('',#459,.T.);
#461=DIRECTION('',(0.,1.,0.));
#462=VECTOR('',#461,1.);
#463=CARTESIAN_POINT('',(0.,-7.33234841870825,-12.7));
#464=LINE('',#463,#462);
#465=CARTESIAN_POINT('',(0.,7.33234841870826,-12.7));
#466=VERTEX_POINT('',#465);
#467=EDGE_CURVE('E131',#417,#466,#464,.T.);
#468=ORIENTED_EDGE('',*,*,#467,.T.);
#469=DIRECTION('',(-1.,0.,0.));
#470=VECTOR('',#469,1.);
#471=CARTESIAN_POINT('',(42.0624,7.33234841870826,-12.7));
#472=LINE('',#471,#470);
#473=CARTESIAN_POINT('',(42.0624,7.33234841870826,-12.7));
#474=VERTEX_POINT('',#473);
#475=EDGE_CURVE('E116',#474,#466,#472,.T.);
#476=ORIENTED_EDGE('',*,*,#475,.F.);
#477=DIRECTION('',(0.,1.,0.));
#478=VECTOR('',#477,1.);
#479=CARTESIAN_POINT('',(42.0624,-7.33234841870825,-12.7));
#480=LINE('',#479,#478);
#481=EDGE_CURVE('E107',#425,#474,#480,.T.);
#482=ORIENTED_EDGE('',*,*,#481,.F.);
#483=ORIENTED_EDGE('',*,*,#426,.T.);
#484=EDGE_LOOP('',(#468,#476,#482,#483));
#485=FACE_BOUND('',#484,.T.);
#486=ADVANCED_FACE('F262',(#460,#485),#449,.F.);
#487=CARTESIAN_POINT('',(42.0624,7.33234841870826,-12.7));
#488=DIRECTION('',(0.,-0.866025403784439,0.5));
#489=DIRECTION('',(0.,-0.5,-0.866025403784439));
#490=AXIS2_PLACEMENT_3D('',#487,#488,#489);
#491=PLANE('',#490);
#492=DIRECTION('',(0.,0.5,0.866025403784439));
#493=VECTOR('',#492,1.);
#494=CARTESIAN_POINT('',(0.,7.33234841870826,-12.7));
#495=LINE('',#494,#493);
#496=CARTESIAN_POINT('',(0.,14.6646968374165,0.));
#497=VERTEX_POINT('',#496);
#498=EDGE_CURVE('E115',#466,#497,#495,.T.);
#499=ORIENTED_EDGE('',*,*,#498,.T.);
#500=DIRECTION('',(-1.,0.,0.));
#501=VECTOR('',#500,1.);
#502=CARTESIAN_POINT('',(42.0624,14.6646968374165,0.));
#503=LINE('',#502,#501);
#504=CARTESIAN_POINT('',(42.0624,14.6646968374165,0.));
#505=VERTEX_POINT('',#504);
#506=EDGE_CURVE('E112',#505,#497,#503,.T.);
#507=ORIENTED_EDGE('',*,*,#506,.F.);
#508=DIRECTION('',(0.,0.5,0.866025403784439));
#509=VECTOR('',#508,1.);
#510=CARTESIAN_POINT('',(42.0624,7.33234841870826,-12.7));
#511=LINE('',#510,#509);
#512=EDGE_CURVE('E100',#474,#505,#511,.T.);
#513=ORIENTED_EDGE('',*,*,#512,.F.);
#514=ORIENTED_EDGE('',*,*,#475,.T.);
#515=EDGE_LOOP('',(#499,#507,#513,#514));
#516=FACE_BOUND('',#515,.T.);
#517=ADVANCED_FACE('F113',(#516),#491,.F.);
#518=CARTESIAN_POINT('',(42.0624,14.6646968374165,0.));
#519=DIRECTION('',(0.,-0.866025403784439,-0.5));
#520=DIRECTION('',(0.,0.5,-0.866025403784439));
#521=AXIS2_PLACEMENT_3D('',#518,#519,#520);
#522=PLANE('',#521);
#523=DIRECTION('',(0.,-0.5,0.866025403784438));
#524=VECTOR('',#523,1.);
#525=CARTESIAN_POINT('',(0.,14.6646968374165,0.));
#526=LINE('',#525,#524);
#527=CARTESIAN_POINT('',(0.,7.33234841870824,12.7));
#528=VERTEX_POINT('',#527);
#529=EDGE_CURVE('E78',#497,#528,#526,.T.);
#530=ORIENTED_EDGE('',*,*,#529,.T.);
#531=DIRECTION('',(-1.,0.,0.));
#532=VECTOR('',#531,1.);
#533=CARTESIAN_POINT('',(42.0624,7.33234841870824,12.7));
#534=LINE('',#533,#532);
#535=CARTESIAN_POINT('',(42.0624,7.33234841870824,12.7));
#536=VERTEX_POINT('',#535);
#537=EDGE_CURVE('E117',#536,#528,#534,.T.);
#538=ORIENTED_EDGE('',*,*,#537,.F.);
#539=DIRECTION('',(0.,-0.5,0.866025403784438));
#540=VECTOR('',#539,1.);
#541=CARTESIAN_POINT('',(42.0624,14.6646968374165,0.));
#542=LINE('',#541,#540);
#543=EDGE_CURVE('E105',#505,#536,#542,.T.);
#544=ORIENTED_EDGE('',*,*,#543,.F.);
#545=ORIENTED_EDGE('',*,*,#506,.T.);
#546=EDGE_LOOP('',(#530,#538,#544,#545));
#547=FACE_BOUND('',#546,.T.);
#548=ADVANCED_FACE('F119',(#547),#522,.F.);
#549=CARTESIAN_POINT('',(42.0624,-14.6646968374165,0.));
#550=DIRECTION('',(1.,0.,0.));
#551=DIRECTION('',(0.,0.,-1.));
#552=AXIS2_PLACEMENT_3D('',#549,#550,#551);
#553=PLANE('',#552);
#554=DIRECTION('',(0.,-0.5,-0.866025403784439));
#555=VECTOR('',#554,1.);
#556=CARTESIAN_POINT('',(42.0624,-7.33234841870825,12.7));
#557=LINE('',#556,#555);
#558=CARTESIAN_POINT('',(42.0624,-7.33234841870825,12.7));
#559=VERTEX_POINT('',#558);
#560=EDGE_CURVE('E136',#559,#433,#557,.T.);
#561=ORIENTED_EDGE('',*,*,#560,.T.);
#562=ORIENTED_EDGE('',*,*,#434,.T.);
#563=ORIENTED_EDGE('',*,*,#481,.T.);
#564=ORIENTED_EDGE('',*,*,#512,.T.);
#565=ORIENTED_EDGE('',*,*,#543,.T.);
#566=DIRECTION('',(0.,-1.,0.));
#567=VECTOR('',#566,1.);
#568=CARTESIAN_POINT('',(42.0624,7.33234841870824,12.7));
#569=LINE('',#568,#567);
#570=EDGE_CURVE('E54',#536,#559,#569,.T.);
#571=ORIENTED_EDGE('',*,*,#570,.T.);
#572=EDGE_LOOP('',(#561,#562,#563,#564,#565,#571));
#573=FACE_BOUND('',#572,.T.);
#574=CARTESIAN_POINT('',(42.0624,0.,0.));
#575=DIRECTION('',(1.,0.,0.));
#576=DIRECTION('',(0.,0.,-1.));
#577=AXIS2_PLACEMENT_3D('',#574,#575,#576);
#578=CIRCLE('',#577,11.1125);
#579=CARTESIAN_POINT('',(42.0624,0.,11.1125));
#580=VERTEX_POINT('',#579);
#581=EDGE_CURVE('E129',#580,#580,#578,.F.);
#582=ORIENTED_EDGE('',*,*,#581,.T.);
#583=EDGE_LOOP('',(#582));
#584=FACE_BOUND('',#583,.T.);
#585=ADVANCED_FACE('F102',(#573,#584),#553,.T.);
#586=CARTESIAN_POINT('',(42.0624,-7.33234841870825,12.7));
#587=DIRECTION('',(0.,0.866025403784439,-0.5));
#588=DIRECTION('',(0.,0.5,0.866025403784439));
#589=AXIS2_PLACEMENT_3D('',#586,#587,#588);
#590=PLANE('',#589);
#591=DIRECTION('',(0.,-0.5,-0.866025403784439));
#592=VECTOR('',#591,1.);
#593=CARTESIAN_POINT('',(0.,-7.33234841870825,12.7));
#594=LINE('',#593,#592);
#595=CARTESIAN_POINT('',(0.,-7.33234841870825,12.7));
#596=VERTEX_POINT('',#595);
#597=EDGE_CURVE('E125',#596,#415,#594,.T.);
#598=ORIENTED_EDGE('',*,*,#597,.T.);
#599=ORIENTED_EDGE('',*,*,#440,.F.);
#600=ORIENTED_EDGE('',*,*,#560,.F.);
#601=DIRECTION('',(-1.,0.,0.));
#602=VECTOR('',#601,1.);
#603=CARTESIAN_POINT('',(42.0624,-7.33234841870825,12.7));
#604=LINE('',#603,#602);
#605=EDGE_CURVE('E121',#559,#596,#604,.T.);
#606=ORIENTED_EDGE('',*,*,#605,.T.);
#607=EDGE_LOOP('',(#598,#599,#600,#606));
#608=FACE_BOUND('',#607,.T.);
#609=ADVANCED_FACE('F37',(#608),#590,.F.);
#610=CARTESIAN_POINT('',(0.,-14.6646968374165,0.));
#611=DIRECTION('',(1.,0.,0.));
#612=DIRECTION('',(0.,0.,-1.));
#613=AXIS2_PLACEMENT_3D('',#610,#611,#612);
#614=PLANE('',#613);
#615=ORIENTED_EDGE('',*,*,#597,.F.);
#616=DIRECTION('',(0.,-1.,0.));
#617=VECTOR('',#616,1.);
#618=CARTESIAN_POINT('',(0.,7.33234841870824,12.7));
#619=LINE('',#618,#617);
#620=EDGE_CURVE('E84',#528,#596,#619,.T.);
#621=ORIENTED_EDGE('',*,*,#620,.F.);
#622=ORIENTED_EDGE('',*,*,#529,.F.);
#623=ORIENTED_EDGE('',*,*,#498,.F.);
#624=ORIENTED_EDGE('',*,*,#467,.F.);
#625=ORIENTED_EDGE('',*,*,#418,.F.);
#626=EDGE_LOOP('',(#615,#621,#622,#623,#624,#625));
#627=FACE_BOUND('',#626,.T.);
#628=ADVANCED_FACE('F251',(#627),#614,.F.);
#629=CARTESIAN_POINT('',(42.0624,7.33234841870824,12.7));
#630=DIRECTION('',(0.,0.,-1.));
#631=DIRECTION('',(0.,1.,0.));
#632=AXIS2_PLACEMENT_3D('',#629,#630,#631);
#633=PLANE('',#632);
#634=CARTESIAN_POINT('',(8.128,0.,12.7));
#635=DIRECTION('',(0.,0.,1.));
#636=DIRECTION('',(1.,0.,0.));
#637=AXIS2_PLACEMENT_3D('',#634,#635,#636);
#638=CIRCLE('',#637,5.1435);
#639=CARTESIAN_POINT('',(13.2715,0.,12.7));
#640=VERTEX_POINT('',#639);
#641=EDGE_CURVE('E299',#640,#640,#638,.T.);
#642=ORIENTED_EDGE('',*,*,#641,.F.);
#643=EDGE_LOOP('',(#642));
#644=FACE_BOUND('',#643,.T.);
#645=ORIENTED_EDGE('',*,*,#400,.F.);
#646=EDGE_LOOP('',(#645));
#647=FACE_BOUND('',#646,.T.);
#648=ORIENTED_EDGE('',*,*,#620,.T.);
#649=ORIENTED_EDGE('',*,*,#605,.F.);
#650=ORIENTED_EDGE('',*,*,#570,.F.);
#651=ORIENTED_EDGE('',*,*,#537,.T.);
#652=EDGE_LOOP('',(#648,#649,#650,#651));
#653=FACE_BOUND('',#652,.T.);
#654=ADVANCED_FACE('F247',(#644,#647,#653),#633,.F.);
#655=CARTESIAN_POINT('',(52.9844,0.,0.));
#656=DIRECTION('',(-1.,0.,0.));
#657=DIRECTION('',(0.,0.,1.));
#658=AXIS2_PLACEMENT_3D('',#655,#656,#657);
#659=CYLINDRICAL_SURFACE('',#658,11.1125);
#660=CARTESIAN_POINT('',(42.0624,0.,11.1125));
#661=CARTESIAN_POINT('',(42.1761708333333,0.,11.1125));
#662=CARTESIAN_POINT('',(42.2899416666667,0.,11.1125));
#663=CARTESIAN_POINT('',(42.5174833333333,0.,11.1125));
#664=CARTESIAN_POINT('',(42.6312541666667,0.,11.1125));
#665=CARTESIAN_POINT('',(42.8587958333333,0.,11.1125));
#666=CARTESIAN_POINT('',(42.9725666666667,0.,11.1125));
#667=CARTESIAN_POINT('',(43.2001083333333,0.,11.1125));
#668=CARTESIAN_POINT('',(43.3138791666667,0.,11.1125));
#669=CARTESIAN_POINT('',(43.5414208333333,0.,11.1125));
#670=CARTESIAN_POINT('',(43.6551916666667,0.,11.1125));
#671=CARTESIAN_POINT('',(43.8827333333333,0.,11.1125));
#672=CARTESIAN_POINT('',(43.9965041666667,0.,11.1125));
#673=CARTESIAN_POINT('',(44.2240458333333,0.,11.1125));
#674=CARTESIAN_POINT('',(44.3378166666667,0.,11.1125));
#675=CARTESIAN_POINT('',(44.5653583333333,0.,11.1125));
#676=CARTESIAN_POINT('',(44.6791291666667,0.,11.1125));
#677=CARTESIAN_POINT('',(44.9066708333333,0.,11.1125));
#678=CARTESIAN_POINT('',(45.0204416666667,0.,11.1125));
#679=CARTESIAN_POINT('',(45.2479833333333,0.,11.1125));
#680=CARTESIAN_POINT('',(45.3617541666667,0.,11.1125));
#681=CARTESIAN_POINT('',(45.5892958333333,0.,11.1125));
#682=CARTESIAN_POINT('',(45.7030666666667,0.,11.1125));
#683=CARTESIAN_POINT('',(45.9306083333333,0.,11.1125));
#684=CARTESIAN_POINT('',(46.0443791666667,0.,11.1125));
#685=CARTESIAN_POINT('',(46.2719208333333,0.,11.1125));
#686=CARTESIAN_POINT('',(46.3856916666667,0.,11.1125));
#687=CARTESIAN_POINT('',(46.6132333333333,0.,11.1125));
#688=CARTESIAN_POINT('',(46.7270041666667,0.,11.1125));
#689=CARTESIAN_POINT('',(46.9545458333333,0.,11.1125));
#690=CARTESIAN_POINT('',(47.0683166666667,0.,11.1125));
#691=CARTESIAN_POINT('',(47.2958583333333,0.,11.1125));
#692=CARTESIAN_POINT('',(47.4096291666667,0.,11.1125));
#693=CARTESIAN_POINT('',(47.6371708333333,0.,11.1125));
#694=CARTESIAN_POINT('',(47.7509416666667,0.,11.1125));
#695=CARTESIAN_POINT('',(47.9784833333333,0.,11.1125));
#696=CARTESIAN_POINT('',(48.0922541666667,0.,11.1125));
#697=CARTESIAN_POINT('',(48.3197958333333,0.,11.1125));
#698=CARTESIAN_POINT('',(48.4335666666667,0.,11.1125));
#699=CARTESIAN_POINT('',(48.6611083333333,0.,11.1125));
#700=CARTESIAN_POINT('',(48.7748791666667,0.,11.1125));
#701=CARTESIAN_POINT('',(49.0024208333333,0.,11.1125));
#702=CARTESIAN_POINT('',(49.1161916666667,0.,11.1125));
#703=CARTESIAN_POINT('',(49.3437333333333,0.,11.1125));
#704=CARTESIAN_POINT('',(49.4575041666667,0.,11.1125));
#705=CARTESIAN_POINT('',(49.6850458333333,0.,11.1125));
#706=CARTESIAN_POINT('',(49.7988166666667,0.,11.1125));
#707=CARTESIAN_POINT('',(50.0263583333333,0.,11.1125));
#708=CARTESIAN_POINT('',(50.1401291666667,0.,11.1125));
#709=CARTESIAN_POINT('',(50.3676708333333,0.,11.1125));
#710=CARTESIAN_POINT('',(50.4814416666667,0.,11.1125));
#711=CARTESIAN_POINT('',(50.7089833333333,0.,11.1125));
#712=CARTESIAN_POINT('',(50.8227541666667,0.,11.1125));
#713=CARTESIAN_POINT('',(51.0502958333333,0.,11.1125));
#714=CARTESIAN_POINT('',(51.1640666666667,0.,11.1125));
#715=CARTESIAN_POINT('',(51.3916083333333,0.,11.1125));
#716=CARTESIAN_POINT('',(51.5053791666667,0.,11.1125));
#717=CARTESIAN_POINT('',(51.7329208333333,0.,11.1125));
#718=CARTESIAN_POINT('',(51.8466916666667,0.,11.1125));
#719=CARTESIAN_POINT('',(52.0742333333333,0.,11.1125));
#720=CARTESIAN_POINT('',(52.1880041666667,0.,11.1125));
#721=CARTESIAN_POINT('',(52.4155458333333,0.,11.1125));
#722=CARTESIAN_POINT('',(52.5293166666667,0.,11.1125));
#723=CARTESIAN_POINT('',(52.7568583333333,0.,11.1125));
#724=CARTESIAN_POINT('',(52.8706291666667,0.,11.1125));
#725=CARTESIAN_POINT('',(52.9844,0.,11.1125));
#726=B_SPLINE_CURVE_WITH_KNOTS('',3,(#660,#661,#662,#663,#664,#665,#666,#667,#668,#669,#670,
#671,#672,#673,#674,#675,#676,#677,#678,#679,#680,#681,#682,#683,#684,#685,#686,#687,#688,#689,
#690,#691,#692,#693,#694,#695,#696,#697,#698,#699,#700,#701,#702,#703,#704,#705,#706,#707,#708,
#709,#710,#711,#712,#713,#714,#715,#716,#717,#718,#719,#720,#721,#722,#723,#724,#725),
.UNSPECIFIED.,.F.,.F.,(4,2,2,2,2,2,2,2,2,2,2,2,2,2,2,2,2,2,2,2,2,2,2,2,2,2,2,2,2,2,2,2,4),(0.,
0.341312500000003,0.682624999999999,1.0239375,1.36525000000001,1.7065625,2.047875,2.3891875,
2.7305,3.0718125,3.413125,3.7544375,4.09575,4.4370625,4.778375,5.1196875,5.461,5.8023125,
6.143625,6.4849375,6.82625,7.1675625,7.508875,7.8501875,8.1915,8.5328125,8.874125,9.2154375,
9.55675,9.8980625,10.239375,10.5806875,10.922),.UNSPECIFIED.);
#727=EDGE_CURVE('BSEAM173',#580,#224,#726,.T.);
#728=ORIENTED_EDGE('',*,*,#581,.F.);
#729=ORIENTED_EDGE('',*,*,#225,.F.);
#730=ORIENTED_EDGE('',*,*,#727,.T.);
#731=ORIENTED_EDGE('',*,*,#727,.F.);
#732=EDGE_LOOP('',(#728,#730,#729,#731));
#733=FACE_BOUND('',#732,.T.);
#734=ADVANCED_FACE('F173',(#733),#659,.T.);
#735=CARTESIAN_POINT('',(8.128,0.,12.7));
#736=DIRECTION('',(0.,0.,1.));
#737=DIRECTION('',(1.,0.,0.));
#738=AXIS2_PLACEMENT_3D('',#735,#736,#737);
#739=CYLINDRICAL_SURFACE('',#738,4.2164);
#740=CARTESIAN_POINT('',(8.128,0.,5.77596));
#741=DIRECTION('',(0.,0.,1.));
#742=DIRECTION('',(1.,0.,0.));
#743=AXIS2_PLACEMENT_3D('',#740,#741,#742);
#744=CIRCLE('',#743,4.2164);
#745=CARTESIAN_POINT('',(12.3444,0.,5.77596));
#746=VERTEX_POINT('',#745);
#747=EDGE_CURVE('E156',#746,#746,#744,.T.);
#748=ORIENTED_EDGE('',*,*,#747,.T.);
#749=EDGE_LOOP('',(#748));
#750=FACE_BOUND('',#749,.T.);
#751=ORIENTED_EDGE('',*,*,#357,.F.);
#752=EDGE_LOOP('',(#751));
#753=FACE_BOUND('',#752,.T.);
#754=CARTESIAN_POINT('',(8.128,0.,-5.77596));
#755=DIRECTION('',(0.,0.,-1.));
#756=DIRECTION('',(-1.,0.,0.));
#757=AXIS2_PLACEMENT_3D('',#754,#755,#756);
#758=CIRCLE('',#757,4.21640000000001);
#759=CARTESIAN_POINT('',(3.91159999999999,0.,-5.77596));
#760=VERTEX_POINT('',#759);
#761=EDGE_CURVE('E302',#760,#760,#758,.T.);
#762=ORIENTED_EDGE('',*,*,#761,.T.);
#763=EDGE_LOOP('',(#762));
#764=FACE_BOUND('',#763,.T.);
#765=ADVANCED_FACE('F167',(#750,#753,#764),#739,.F.);
#766=CARTESIAN_POINT('',(12.3444,0.,5.77596));
#767=DIRECTION('',(0.,0.,-1.));
#768=DIRECTION('',(-1.,0.,0.));
#769=AXIS2_PLACEMENT_3D('',#766,#767,#768);
#770=PLANE('',#769);
#771=ORIENTED_EDGE('',*,*,#747,.F.);
#772=EDGE_LOOP('',(#771));
#773=FACE_BOUND('',#772,.T.);
#774=CARTESIAN_POINT('',(8.128,0.,5.77596));
#775=DIRECTION('',(0.,0.,1.));
#776=DIRECTION('',(1.,0.,0.));
#777=AXIS2_PLACEMENT_3D('',#774,#775,#776);
#778=CIRCLE('',#777,4.93618496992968);
#779=CARTESIAN_POINT('',(13.0641849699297,0.,5.77596));
#780=VERTEX_POINT('',#779);
#781=EDGE_CURVE('E296',#780,#780,#778,.T.);
#782=ORIENTED_EDGE('',*,*,#781,.T.);
#783=EDGE_LOOP('',(#782));
#784=FACE_BOUND('',#783,.T.);
#785=ADVANCED_FACE('F172',(#773,#784),#770,.F.);
#786=CARTESIAN_POINT('',(8.128,0.,12.7));
#787=DIRECTION('',(0.,0.,1.));
#788=DIRECTION('',(1.,0.,0.));
#789=AXIS2_PLACEMENT_3D('',#786,#787,#788);
#790=CONICAL_SURFACE('',#789,5.1435,0.0299323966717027);
#791=ORIENTED_EDGE('',*,*,#781,.F.);
#792=EDGE_LOOP('',(#791));
#793=FACE_BOUND('',#792,.T.);
#794=ORIENTED_EDGE('',*,*,#641,.T.);
#795=EDGE_LOOP('',(#794));
#796=FACE_BOUND('',#795,.T.);
#797=ADVANCED_FACE('F218',(#793,#796),#790,.F.);
#798=CARTESIAN_POINT('',(12.3444,0.,-5.77596));
#799=DIRECTION('',(0.,0.,1.));
#800=DIRECTION('',(1.,0.,0.));
#801=AXIS2_PLACEMENT_3D('',#798,#799,#800);
#802=PLANE('',#801);
#803=ORIENTED_EDGE('',*,*,#761,.F.);
#804=EDGE_LOOP('',(#803));
#805=FACE_BOUND('',#804,.T.);
#806=CARTESIAN_POINT('',(8.128,0.,-5.77596));
#807=DIRECTION('',(0.,0.,-1.));
#808=DIRECTION('',(-1.,0.,0.));
#809=AXIS2_PLACEMENT_3D('',#806,#807,#808);
#810=CIRCLE('',#809,4.93618496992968);
#811=CARTESIAN_POINT('',(3.19181503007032,0.,-5.77596));
#812=VERTEX_POINT('',#811);
#813=EDGE_CURVE('E305',#812,#812,#810,.T.);
#814=ORIENTED_EDGE('',*,*,#813,.T.);
#815=EDGE_LOOP('',(#814));
#816=FACE_BOUND('',#815,.T.);
#817=ADVANCED_FACE('F215',(#805,#816),#802,.F.);
#818=CARTESIAN_POINT('',(8.128,0.,-12.7));
#819=DIRECTION('',(0.,0.,-1.));
#820=DIRECTION('',(-1.,0.,0.));
#821=AXIS2_PLACEMENT_3D('',#818,#819,#820);
#822=CONICAL_SURFACE('',#821,5.1435,0.0299323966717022);
#823=ORIENTED_EDGE('',*,*,#813,.F.);
#824=EDGE_LOOP('',(#823));
#825=FACE_BOUND('',#824,.T.);
#826=ORIENTED_EDGE('',*,*,#457,.T.);
#827=EDGE_LOOP('',(#826));
#828=FACE_BOUND('',#827,.T.);
#829=ADVANCED_FACE('F208',(#825,#828),#822,.F.);
#830=CARTESIAN_POINT('',(27.5844,0.,0.));
#831=DIRECTION('',(1.,0.,0.));
#832=DIRECTION('',(0.,0.,-1.));
#833=AXIS2_PLACEMENT_3D('',#830,#831,#832);
#834=PLANE('',#833);
#835=CARTESIAN_POINT('',(27.5844,0.,0.));
#836=DIRECTION('',(-1.,0.,0.));
#837=DIRECTION('',(0.,0.,1.));
#838=AXIS2_PLACEMENT_3D('',#835,#836,#837);
#839=CIRCLE('',#838,5.54990000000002);
#840=CARTESIAN_POINT('',(27.5844,0.,5.54990000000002));
#841=VERTEX_POINT('',#840);
#842=EDGE_CURVE('E314',#841,#841,#839,.T.);
#843=ORIENTED_EDGE('',*,*,#842,.F.);
#844=EDGE_LOOP('',(#843));
#845=FACE_BOUND('',#844,.T.);
#846=ORIENTED_EDGE('',*,*,#42,.T.);
#847=EDGE_LOOP('',(#846));
#848=FACE_BOUND('',#847,.T.);
#849=ADVANCED_FACE('F202',(#845,#848),#834,.T.);
#850=CARTESIAN_POINT('',(0.,0.,0.));
#851=DIRECTION('',(-1.,0.,0.));
#852=DIRECTION('',(0.,0.,1.));
#853=AXIS2_PLACEMENT_3D('',#850,#851,#852);
#854=CYLINDRICAL_SURFACE('',#853,5.54990000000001);
#855=ORIENTED_EDGE('',*,*,#842,.T.);
#856=EDGE_LOOP('',(#855));
#857=FACE_BOUND('',#856,.T.);
#858=CARTESIAN_POINT('',(45.0596,0.,0.));
#859=DIRECTION('',(-1.,0.,0.));
#860=DIRECTION('',(0.,0.,1.));
#861=AXIS2_PLACEMENT_3D('',#858,#859,#860);
#862=CIRCLE('',#861,5.54990000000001);
#863=CARTESIAN_POINT('',(45.0596,0.,5.54990000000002));
#864=VERTEX_POINT('',#863);
#865=EDGE_CURVE('E317',#864,#864,#862,.T.);
#866=ORIENTED_EDGE('',*,*,#865,.F.);
#867=EDGE_LOOP('',(#866));
#868=FACE_BOUND('',#867,.T.);
#869=ORIENTED_EDGE('',*,*,#208,.T.);
#870=EDGE_LOOP('',(#869));
#871=FACE_BOUND('',#870,.T.);
#872=CARTESIAN_POINT('',(37.7444,0.,-5.54990000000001));
#873=CARTESIAN_POINT('',(37.7443993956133,-0.102666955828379,-5.54989942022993));
#874=CARTESIAN_POINT('',(37.7406438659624,-0.205343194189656,-5.54704470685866));
#875=CARTESIAN_POINT('',(37.7256842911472,-0.409877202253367,-5.53569249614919));
#876=CARTESIAN_POINT('',(37.7144766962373,-0.511734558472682,-5.52719230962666));
#877=CARTESIAN_POINT('',(37.6847756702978,-0.713930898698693,-5.50472974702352));
#878=CARTESIAN_POINT('',(37.6662712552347,-0.814267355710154,-5.49075913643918));
#879=CARTESIAN_POINT('',(37.6222775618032,-1.01254840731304,-5.45767930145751));
#880=CARTESIAN_POINT('',(37.5967851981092,-1.11049192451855,-5.4385678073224));
#881=CARTESIAN_POINT('',(37.5107274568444,-1.398497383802,-5.37438339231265));
#882=CARTESIAN_POINT('',(37.440361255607,-1.58418379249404,-5.32229076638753));
#883=CARTESIAN_POINT('',(37.276841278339,-1.93974746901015,-5.20327185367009));
#884=CARTESIAN_POINT('',(37.1836912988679,-2.10962736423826,-5.13634803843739));
#885=CARTESIAN_POINT('',(36.9680945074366,-2.44693461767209,-4.98509307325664));
#886=CARTESIAN_POINT('',(36.8437265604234,-2.61265837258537,-4.89972096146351));
#887=CARTESIAN_POINT('',(36.5743774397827,-2.92229860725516,-4.72159970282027));
#888=CARTESIAN_POINT('',(36.4293655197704,-3.06618188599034,-4.62883964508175));
#889=CARTESIAN_POINT('',(36.1818679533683,-3.27873581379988,-4.47894046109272));
#890=CARTESIAN_POINT('',(36.0852396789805,-3.35465016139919,-4.42221951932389));
#891=CARTESIAN_POINT('',(35.8853172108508,-3.49803153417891,-4.30969399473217));
#892=CARTESIAN_POINT('',(35.7820209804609,-3.56549595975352,-4.25388969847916));
#893=CARTESIAN_POINT('',(35.5689644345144,-3.69158445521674,-4.14494021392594));
#894=CARTESIAN_POINT('',(35.459210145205,-3.75021659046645,-4.09179262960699));
#895=CARTESIAN_POINT('',(35.2332788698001,-3.85820397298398,-3.99013143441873));
#896=CARTESIAN_POINT('',(35.1171056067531,-3.90756452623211,-3.94161518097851));
#897=CARTESIAN_POINT('',(34.8423535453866,-4.00972513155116,-3.8380021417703));
#898=CARTESIAN_POINT('',(34.6815147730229,-4.05910874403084,-3.78530268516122));
#899=CARTESIAN_POINT('',(34.4334747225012,-4.11890503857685,-3.71979682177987));
#900=CARTESIAN_POINT('',(34.3497154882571,-4.13645117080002,-3.70022626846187));
#901=CARTESIAN_POINT('',(34.1802742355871,-4.16652842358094,-3.66632583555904));
#902=CARTESIAN_POINT('',(34.0945932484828,-4.17906216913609,-3.65199321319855));
#903=CARTESIAN_POINT('',(33.9209530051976,-4.19896788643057,-3.62908998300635));
#904=CARTESIAN_POINT('',(33.8329793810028,-4.2062854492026,-3.62058014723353));
#905=CARTESIAN_POINT('',(33.6563570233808,-4.2153732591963,-3.60999553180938));
#906=CARTESIAN_POINT('',(33.5677083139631,-4.21714370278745,-3.60792052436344));
#907=CARTESIAN_POINT('',(33.3905433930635,-4.21508975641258,-3.61032018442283));
#908=CARTESIAN_POINT('',(33.3020272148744,-4.21126414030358,-3.61479628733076));
#909=CARTESIAN_POINT('',(33.1259748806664,-4.1981195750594,-3.63005192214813));
#910=CARTESIAN_POINT('',(33.0384387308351,-4.18880059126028,-3.64083149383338));
#911=CARTESIAN_POINT('',(32.7985166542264,-4.15568903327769,-3.67868158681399));
#912=CARTESIAN_POINT('',(32.6478348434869,-4.1262776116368,-3.71190594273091));
#913=CARTESIAN_POINT('',(32.3540921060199,-4.05253036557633,-3.79227022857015));
#914=CARTESIAN_POINT('',(32.211039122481,-4.00817932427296,-3.83942434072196));
#915=CARTESIAN_POINT('',(31.9583831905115,-3.91523448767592,-3.93394303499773));
#916=CARTESIAN_POINT('',(31.847374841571,-3.86881960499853,-3.97976043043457));
#917=CARTESIAN_POINT('',(31.6311954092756,-3.76754813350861,-4.07576238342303));
#918=CARTESIAN_POINT('',(31.5260274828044,-3.71268703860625,-4.12594926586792));
#919=CARTESIAN_POINT('',(31.3214051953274,-3.59484859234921,-4.22901830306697));
#920=CARTESIAN_POINT('',(31.2219633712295,-3.53185434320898,-4.28190592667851));
#921=CARTESIAN_POINT('',(31.0290973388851,-3.39812936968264,-4.38878526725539));
#922=CARTESIAN_POINT('',(30.9356721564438,-3.32739990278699,-4.44277680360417));
#923=CARTESIAN_POINT('',(30.75235900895,-3.17621734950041,-4.5521400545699));
#924=CARTESIAN_POINT('',(30.6626496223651,-3.0955433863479,-4.6075068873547));
#925=CARTESIAN_POINT('',(30.4900225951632,-2.92631985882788,-4.71680129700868));
#926=CARTESIAN_POINT('',(30.4071076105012,-2.83776724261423,-4.77072830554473));
#927=CARTESIAN_POINT('',(30.1695373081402,-2.5608184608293,-4.92833957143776));
#928=CARTESIAN_POINT('',(30.0255232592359,-2.36069403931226,-5.02818332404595));
#929=CARTESIAN_POINT('',(29.79622654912,-1.97290355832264,-5.19079382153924));
#930=CARTESIAN_POINT('',(29.704976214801,-1.7902262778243,-5.25699864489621));
#931=CARTESIAN_POINT('',(29.5877201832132,-1.50428240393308,-5.34307696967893));
#932=CARTESIAN_POINT('',(29.5518975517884,-1.40695118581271,-5.36957042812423));
#933=CARTESIAN_POINT('',(29.487255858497,-1.20882529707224,-5.41761054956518));
#934=CARTESIAN_POINT('',(29.4584337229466,-1.10803216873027,-5.43915938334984));
#935=CARTESIAN_POINT('',(29.4080388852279,-0.902877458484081,-5.47696644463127));
#936=CARTESIAN_POINT('',(29.3865198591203,-0.798495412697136,-5.49318547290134));
#937=CARTESIAN_POINT('',(29.3513945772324,-0.587711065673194,-5.51971567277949));
#938=CARTESIAN_POINT('',(29.3377846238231,-0.481309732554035,-5.53002960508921));
#939=CARTESIAN_POINT('',(29.3187165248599,-0.267379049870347,-5.54449183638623));
#940=CARTESIAN_POINT('',(29.3132569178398,-0.159849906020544,-5.54864124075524));
#941=CARTESIAN_POINT('',(29.31059043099,0.0553630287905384,-5.55066695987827));
#942=CARTESIAN_POINT('',(29.3133828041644,0.163046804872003,-5.54854384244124));
#943=CARTESIAN_POINT('',(29.3264157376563,0.365919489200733,-5.53865106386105));
#944=CARTESIAN_POINT('',(29.3358141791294,0.461194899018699,-5.53151989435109));
#945=CARTESIAN_POINT('',(29.3609746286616,0.650427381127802,-5.51247648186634));
#946=CARTESIAN_POINT('',(29.3767386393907,0.744384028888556,-5.50056273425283));
#947=CARTESIAN_POINT('',(29.4332697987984,1.02327908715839,-5.4579792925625));
#948=CARTESIAN_POINT('',(29.4832871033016,1.20540685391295,-5.42045882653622));
#949=CARTESIAN_POINT('',(29.6070842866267,1.56242729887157,-5.32871242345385));
#950=CARTESIAN_POINT('',(29.681457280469,1.73700152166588,-5.27407116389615));
#951=CARTESIAN_POINT('',(29.8505450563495,2.07109183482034,-5.15204916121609));
#952=CARTESIAN_POINT('',(29.9452628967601,2.23060565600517,-5.08466650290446));
#953=CARTESIAN_POINT('',(30.1694079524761,2.55802504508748,-4.92909083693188));
#954=CARTESIAN_POINT('',(30.3019810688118,2.72300325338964,-4.83929765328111));
#955=CARTESIAN_POINT('',(30.5883037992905,3.02991540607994,-4.65330404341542));
#956=CARTESIAN_POINT('',(30.7420960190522,3.1718017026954,-4.55709093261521));
#957=CARTESIAN_POINT('',(31.0034639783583,3.37940703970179,-4.40345363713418));
#958=CARTESIAN_POINT('',(31.1049126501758,3.45288781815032,-4.34591141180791));
#959=CARTESIAN_POINT('',(31.314685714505,3.59096735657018,-4.23253042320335));
#960=CARTESIAN_POINT('',(31.4230125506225,3.65556293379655,-4.17669227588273));
#961=CARTESIAN_POINT('',(31.6462598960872,3.77532660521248,-4.06875742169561));
#962=CARTESIAN_POINT('',(31.7611678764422,3.83051186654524,-4.01665400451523));
#963=CARTESIAN_POINT('',(31.9975785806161,3.93094643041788,-3.91841531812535));
#964=CARTESIAN_POINT('',(32.1190762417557,3.97620322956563,-3.8722755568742));
#965=CARTESIAN_POINT('',(32.3974988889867,4.06520982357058,-3.7789612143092));
#966=CARTESIAN_POINT('',(32.5561211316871,4.10619306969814,-3.7340128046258));
#967=CARTESIAN_POINT('',(32.7996105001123,4.15383268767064,-3.6807099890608));
#968=CARTESIAN_POINT('',(32.8816471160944,4.16740255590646,-3.66530086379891));
#969=CARTESIAN_POINT('',(33.0471718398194,4.18972486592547,-3.63976459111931));
#970=CARTESIAN_POINT('',(33.1306592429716,4.19847958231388,-3.62963494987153));
#971=CARTESIAN_POINT('',(33.2991320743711,4.21103758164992,-3.61505835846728));
#972=CARTESIAN_POINT('',(33.3841240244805,4.21480358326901,-3.61065420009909));
#973=CARTESIAN_POINT('',(33.5542775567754,4.21717640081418,-3.60788260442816));
#974=CARTESIAN_POINT('',(33.639439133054,4.21578339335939,-3.60951496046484));
#975=CARTESIAN_POINT('',(33.8092521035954,4.20786839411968,-3.61873867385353));
#976=CARTESIAN_POINT('',(33.8939031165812,4.20134295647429,-3.62633403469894));
#977=CARTESIAN_POINT('',(34.0620056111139,4.18330254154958,-3.64713005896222));
#978=CARTESIAN_POINT('',(34.1454564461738,4.1717849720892,-3.66033363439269));
#979=CARTESIAN_POINT('',(34.3240534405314,4.14171556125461,-3.69434379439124));
#980=CARTESIAN_POINT('',(34.4188890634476,4.12232321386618,-3.71603879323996));
#981=CARTESIAN_POINT('',(34.6056232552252,4.07749843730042,-3.76516999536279));
#982=CARTESIAN_POINT('',(34.697519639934,4.05206162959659,-3.79261035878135));
#983=CARTESIAN_POINT('',(34.9685718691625,3.96719813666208,-3.88193715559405));
#984=CARTESIAN_POINT('',(35.1428493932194,3.89926066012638,-3.95077814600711));
#985=CARTESIAN_POINT('',(35.4260549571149,3.76720881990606,-4.07616702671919));
#986=CARTESIAN_POINT('',(35.5387046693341,3.70824622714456,-4.13006200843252));
#987=CARTESIAN_POINT('',(35.7572672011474,3.58111275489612,-4.24076863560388));
#988=CARTESIAN_POINT('',(35.8631775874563,3.51293857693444,-4.29758132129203));
#989=CARTESIAN_POINT('',(36.0681950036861,3.36767607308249,-4.41233843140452));
#990=CARTESIAN_POINT('',(36.167295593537,3.29057948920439,-4.47028386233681));
#991=CARTESIAN_POINT('',(36.3583871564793,3.12772920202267,-4.58570164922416));
#992=CARTESIAN_POINT('',(36.4503790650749,3.0419766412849,-4.64317406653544));
#993=CARTESIAN_POINT('',(36.6281804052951,2.86064113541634,-4.75707411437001));
#994=CARTESIAN_POINT('',(36.7138800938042,2.76493305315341,-4.81347428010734));
#995=CARTESIAN_POINT('',(36.8770160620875,2.56491197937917,-4.92296818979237));
#996=CARTESIAN_POINT('',(36.954451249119,2.46059785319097,-4.97606149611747));
#997=CARTESIAN_POINT('',(37.100127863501,2.24386878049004,-5.07747289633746));
#998=CARTESIAN_POINT('',(37.1683863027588,2.13146943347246,-5.12579978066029));
#999=CARTESIAN_POINT('',(37.29491910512,1.89890802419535,-5.21642520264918));
#1000=CARTESIAN_POINT('',(37.3531981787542,1.77874966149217,-5.25872658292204));
#1001=CARTESIAN_POINT('',(37.4439058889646,1.56622364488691,-5.32513054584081));
#1002=CARTESIAN_POINT('',(37.4789964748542,1.4755360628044,-5.35100662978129));
#1003=CARTESIAN_POINT('',(37.5430944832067,1.29096184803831,-5.39850728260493));
#1004=CARTESIAN_POINT('',(37.5721033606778,1.19707598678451,-5.42013286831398));
#1005=CARTESIAN_POINT('',(37.6236159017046,1.0068038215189,-5.45867560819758));
#1006=CARTESIAN_POINT('',(37.6461329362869,0.910423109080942,-5.47560243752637));
#1007=CARTESIAN_POINT('',(37.6844114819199,0.715624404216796,-5.50444899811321));
#1008=CARTESIAN_POINT('',(37.700175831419,0.617207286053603,-5.51637083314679));
#1009=CARTESIAN_POINT('',(37.7230526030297,0.432452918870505,-5.53369497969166));
#1010=CARTESIAN_POINT('',(37.7310480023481,0.346286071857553,-5.53976185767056));
#1011=CARTESIAN_POINT('',(37.7417225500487,0.173415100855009,-5.54786506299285));
#1012=CARTESIAN_POINT('',(37.7444005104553,0.0867108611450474,-5.5499004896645));
#1013=CARTESIAN_POINT('',(37.7444,0.,-5.54990000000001));
#1014=B_SPLINE_CURVE_WITH_KNOTS('',3,(#872,#873,#874,#875,#876,#877,#878,#879,#880,#881,#882,
#883,#884,#885,#886,#887,#888,#889,#890,#891,#892,#893,#894,#895,#896,#897,#898,#899,#900,#901,
#902,#903,#904,#905,#906,#907,#908,#909,#910,#911,#912,#913,#914,#915,#916,#917,#918,#919,#920,
#921,#922,#923,#924,#925,#926,#927,#928,#929,#930,#931,#932,#933,#934,#935,#936,#937,#938,#939,
#940,#941,#942,#943,#944,#945,#946,#947,#948,#949,#950,#951,#952,#953,#954,#955,#956,#957,#958,
#959,#960,#961,#962,#963,#964,#965,#966,#967,#968,#969,#970,#971,#972,#973,#974,#975,#976,#977,
#978,#979,#980,#981,#982,#983,#984,#985,#986,#987,#988,#989,#990,#991,#992,#993,#994,#995,#996,
#997,#998,#999,#1000,#1001,#1002,#1003,#1004,#1005,#1006,#1007,#1008,#1009,#1010,#1011,#1012,
#1013),.UNSPECIFIED.,.T.,.F.,(4,2,2,2,2,2,2,2,2,2,2,2,2,2,2,2,2,2,2,2,2,2,2,2,2,2,2,2,2,2,2,2,2,
2,2,2,2,2,2,2,2,2,2,2,2,2,2,2,2,2,2,2,2,2,2,2,2,2,2,2,2,2,2,2,2,2,2,2,2,2,4),(0.,
0.307909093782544,0.615964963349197,0.924486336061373,1.23314414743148,1.84608968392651,
2.45893315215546,3.12888302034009,3.79984133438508,4.20549409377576,4.61127134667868,
5.01667578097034,5.42184749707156,5.94866107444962,6.21175949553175,6.4747199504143,
6.7403846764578,7.00603999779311,7.27175353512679,7.53746874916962,8.00678580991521,
8.47658235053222,8.86232249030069,9.24826914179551,9.63503095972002,10.0217299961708,
10.4195319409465,10.817488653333,11.6111347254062,12.2523588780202,12.5731486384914,
12.8937972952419,13.2167540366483,13.5395596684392,13.8623074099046,14.1850259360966,
14.4726847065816,14.7604340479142,15.3354443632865,15.9256524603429,16.5159493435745,
17.2032337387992,17.891918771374,18.3050679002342,18.7183646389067,19.1308991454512,
19.5431210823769,20.0506303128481,20.3040712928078,20.5573924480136,20.8125962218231,
21.0677912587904,21.3231577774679,21.5786570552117,21.8757972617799,22.173153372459,
22.7686074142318,23.1824806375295,23.5965024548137,24.0109105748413,24.4252640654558,
24.8456610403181,25.2661135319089,25.6857755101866,26.1052388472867,26.4068178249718,
26.7083245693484,27.0092058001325,27.3099604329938,27.5699574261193,27.8300124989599),.UNSPECIFIED.);
#1015=CARTESIAN_POINT('',(37.7444,0.,-5.54990000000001));
#1016=VERTEX_POINT('',#1015);
#1017=EDGE_CURVE('E191',#1016,#1016,#1014,.T.);
#1018=ORIENTED_EDGE('',*,*,#1017,.T.);
#1019=EDGE_LOOP('',(#1018));
#1020=FACE_BOUND('',#1019,.T.);
#1021=ADVANCED_FACE('F196',(#857,#868,#871,#1020),#854,.F.);
#1022=CARTESIAN_POINT('',(52.9844,0.,0.));
#1023=DIRECTION('',(1.,0.,0.));
#1024=DIRECTION('',(0.,0.,-1.));
#1025=AXIS2_PLACEMENT_3D('',#1022,#1023,#1024);
#1026=CONICAL_SURFACE('',#1025,6.73100000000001,0.0523598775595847);
#1027=CARTESIAN_POINT('',(45.0595999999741,0.,0.));
#1028=DIRECTION('',(-1.,0.,0.));
#1029=DIRECTION('',(0.,0.,1.));
#1030=AXIS2_PLACEMENT_3D('',#1027,#1028,#1029);
#1031=CIRCLE('',#1030,6.31567883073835);
#1032=CARTESIAN_POINT('',(45.0595999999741,0.,6.31567883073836));
#1033=VERTEX_POINT('',#1032);
#1034=EDGE_CURVE('E320',#1033,#1033,#1031,.T.);
#1035=ORIENTED_EDGE('',*,*,#1034,.T.);
#1036=EDGE_LOOP('',(#1035));
#1037=FACE_BOUND('',#1036,.T.);
#1038=ORIENTED_EDGE('',*,*,#236,.F.);
#1039=EDGE_LOOP('',(#1038));
#1040=FACE_BOUND('',#1039,.T.);
#1041=ADVANCED_FACE('F201',(#1037,#1040),#1026,.F.);
#1042=CARTESIAN_POINT('',(45.059599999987,0.,-5.5499));
#1043=DIRECTION('',(1.,0.,0.));
#1044=DIRECTION('',(0.,0.,-1.));
#1045=AXIS2_PLACEMENT_3D('',#1042,#1043,#1044);
#1046=PLANE('',#1045);
#1047=ORIENTED_EDGE('',*,*,#865,.T.);
#1048=EDGE_LOOP('',(#1047));
#1049=FACE_BOUND('',#1048,.T.);
#1050=ORIENTED_EDGE('',*,*,#1034,.F.);
#1051=EDGE_LOOP('',(#1050));
#1052=FACE_BOUND('',#1051,.T.);
#1053=ADVANCED_FACE('F204',(#1049,#1052),#1046,.T.);
#1054=CARTESIAN_POINT('',(33.528,0.,-6.34999999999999));
#1055=DIRECTION('',(0.,0.,1.));
#1056=DIRECTION('',(1.,0.,0.));
#1057=AXIS2_PLACEMENT_3D('',#1054,#1055,#1056);
#1058=CONICAL_SURFACE('',#1057,4.2164,1.02974425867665);
#1059=CARTESIAN_POINT('',(33.528,0.,-8.8834687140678));
#1060=VERTEX_POINT('',#1059);
#1061=VERTEX_LOOP('',#1060);
#1062=FACE_BOUND('',#1061,.T.);
#1063=CARTESIAN_POINT('',(33.528,0.,-6.34999999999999));
#1064=DIRECTION('',(0.,0.,1.));
#1065=DIRECTION('',(1.,0.,0.));
#1066=AXIS2_PLACEMENT_3D('',#1063,#1064,#1065);
#1067=CIRCLE('',#1066,4.2164);
#1068=CARTESIAN_POINT('',(37.7444,0.,-6.34999999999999));
#1069=VERTEX_POINT('',#1068);
#1070=EDGE_CURVE('E146',#1069,#1069,#1067,.T.);
#1071=ORIENTED_EDGE('',*,*,#1070,.T.);
#1072=EDGE_LOOP('',(#1071));
#1073=FACE_BOUND('',#1072,.T.);
#1074=ADVANCED_FACE('F187',(#1062,#1073),#1058,.F.);
#1075=ORIENTED_EDGE('',*,*,#1070,.F.);
#1076=EDGE_LOOP('',(#1075));
#1077=FACE_BOUND('',#1076,.T.);
#1078=ORIENTED_EDGE('',*,*,#1017,.F.);
#1079=EDGE_LOOP('',(#1078));
#1080=FACE_BOUND('',#1079,.T.);
#1081=ADVANCED_FACE('F184',(#1077,#1080),#51,.F.);
#1082=CLOSED_SHELL('',(#46,#212,#240,#260,#364,#384,#404,#444,#486,#517,#548,#585,#609,#628,
#654,#734,#765,#785,#797,#817,#829,#849,#1021,#1041,#1053,#1074,#1081));
#1083=MANIFOLD_SOLID_BREP('B2',#1082);
#1084=ADVANCED_BREP_SHAPE_REPRESENTATION('',(#18,#1083),#14);
#1085=SHAPE_DEFINITION_REPRESENTATION(#9,#1084);
ENDSEC;
END-ISO-10303-21;
